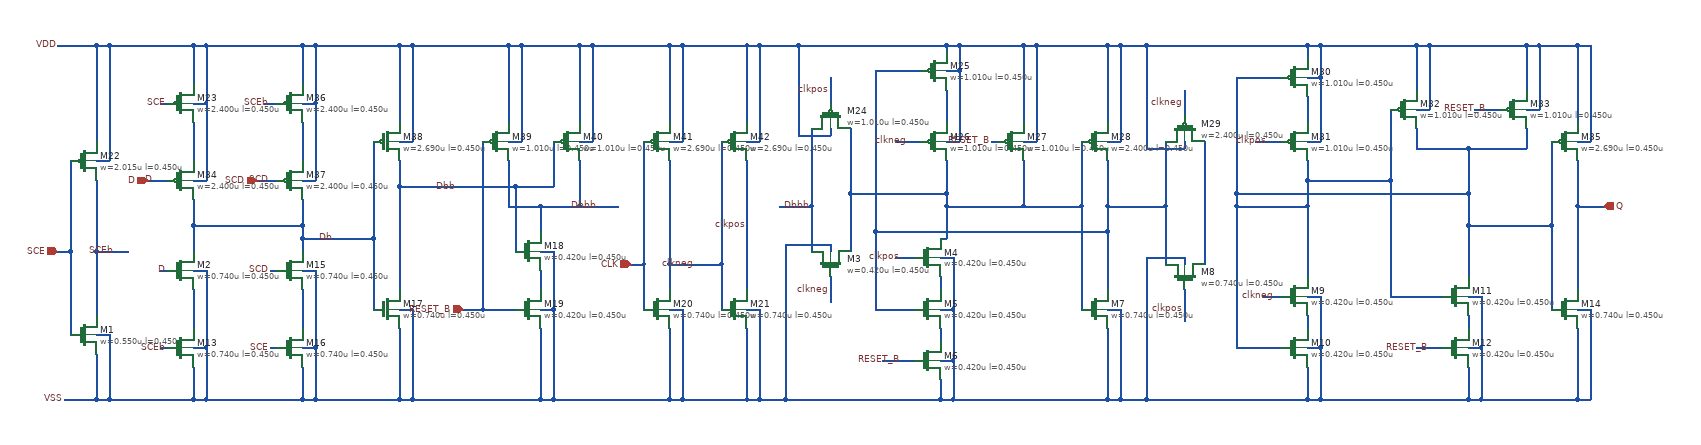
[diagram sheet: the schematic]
v {xschem version=3.4.8RC file_version=1.3}
* Copyright 2023 IHP PDK Authors
*
* Licensed under the Apache License, Version 2.0 (the "License");
* you may not use this file except in compliance with the License.
* You may obtain a copy of the License at
*
*     https://www.apache.org/licenses/LICENSE-2.0
*
* Unless required by applicable law or agreed to in writing, software
* distributed under the License is distributed on an "AS IS" BASIS,
* WITHOUT WARRANTIES OR CONDITIONS OF ANY KIND, either express or implied.
* See the License for the specific language governing permissions and
* limitations under the License.
}

G {}
K {}
V {}
S {}
F {}
E {}
N -270 -3890 -270 -3820 {lab=VSS}
N 50 -4070 50 -4050 {lab=Db}
N -250 -3920 -250 -3820 {lab=VSS}
N 70 -4370 70 -4280 {lab=VDD}
N 70 -4280 70 -4160 {lab=VDD}
N 70 -4020 70 -3900 {lab=VSS}
N 50 -4280 70 -4280 {lab=VDD}
N 50 -4370 70 -4370 {lab=VDD}
N 50 -4020 70 -4020 {lab=VSS}
N 50 -4160 70 -4160 {lab=VDD}
N 50 -3900 70 -3900 {lab=VSS}
N -320 -3820 -270 -3820 {lab=VSS}
N -100 -4370 50 -4370 {lab=VDD}
N -250 -3820 -120 -3820 {lab=VSS}
N 50 -4090 50 -4070 {lab=Db}
N 50 -4370 50 -4310 {lab=VDD}
N 50 -4250 50 -4190 {lab=#net1}
N 50 -3990 50 -3930 {lab=#net2}
N 50 -3870 50 -3820 {lab=VSS}
N -120 -4130 -120 -4090 {lab=Db}
N -120 -4090 50 -4090 {lab=Db}
N -20 -4160 10 -4160 {lab=SCD}
N -170 -3900 -160 -3900 {lab=SCEb}
N 0 -4020 10 -4020 {lab=SCD}
N 0 -3900 10 -3900 {lab=SCE}
N -100 -3820 50 -3820 {lab=VSS}
N 50 -3820 70 -3820 {lab=VSS}
N -100 -4370 -100 -4280 {lab=VDD}
N -100 -4280 -100 -4160 {lab=VDD}
N -100 -4020 -100 -3900 {lab=VSS}
N -120 -4280 -100 -4280 {lab=VDD}
N -120 -4370 -100 -4370 {lab=VDD}
N -120 -4160 -100 -4160 {lab=VDD}
N -120 -3900 -100 -3900 {lab=VSS}
N -270 -3820 -250 -3820 {lab=VSS}
N -120 -4020 -100 -4020 {lab=VSS}
N 70 -3900 70 -3820 {lab=VSS}
N -330 -4370 -270 -4370 {lab=VDD}
N 50 -4070 160 -4070 {lab=Db}
N -120 -4090 -120 -4050 {lab=Db}
N -120 -4370 -120 -4310 {lab=VDD}
N -120 -4250 -120 -4190 {lab=#net3}
N -120 -3990 -120 -3930 {lab=#net4}
N -270 -4370 -250 -4370 {lab=VDD}
N 50 -4130 50 -4090 {lab=Db}
N -190 -4160 -160 -4160 {lab=D}
N -170 -4280 -160 -4280 {lab=SCE}
N -170 -4020 -160 -4020 {lab=D}
N -10 -4280 10 -4280 {lab=SCEb}
N -310 -4050 -310 -3920 {lab=SCE}
N -250 -4370 -250 -4190 {lab=VDD}
N -270 -4190 -250 -4190 {lab=VDD}
N -270 -4050 -220 -4050 {lab=SCEb}
N -120 -3870 -120 -3820 {lab=VSS}
N -270 -3920 -250 -3920 {lab=VSS}
N -270 -4050 -270 -3950 {lab=SCEb}
N -120 -3820 -100 -3820 {lab=VSS}
N -270 -4370 -270 -4220 {lab=VDD}
N -270 -4160 -270 -4050 {lab=SCEb}
N 380 -4150 380 -4050 {lab=Dbb}
N -250 -4370 -120 -4370 {lab=VDD}
N -310 -4190 -310 -4050 {lab=SCE}
N -330 -4050 -310 -4050 {lab=SCE}
N -100 -3900 -100 -3820 {lab=VSS}
N 220 -3820 420 -3820 {lab=VSS}
N 200 -3820 220 -3820 {lab=VSS}
N 1800 -4370 1950 -4370 {lab=VDD}
N 1360 -3820 1610 -3820 {lab=VSS}
N 1780 -4370 1800 -4370 {lab=VDD}
N 1990 -4220 1990 -4090 {lab=#net5}
N 1950 -4370 1970 -4370 {lab=VDD}
N 1950 -4370 1950 -4300 {lab=VDD}
N 940 -4330 940 -4080 {lab=#net6}
N 220 -4370 370 -4370 {lab=VDD}
N 1610 -4120 1610 -4010 {lab=#net5}
N 1780 -4210 1860 -4210 {lab=#net5}
N 2050 -4370 2050 -4220 {lab=VDD}
N 1880 -3820 2030 -3820 {lab=VSS}
N 200 -3960 220 -3960 {lab=VSS}
N 1260 -4220 1260 -4120 {lab=#net7}
N 1170 -4120 1260 -4120 {lab=#net7}
N 390 -4370 480 -4370 {lab=VDD}
N 940 -4330 1010 -4330 {lab=#net6}
N 1300 -4080 1300 -3990 {lab=#net6}
N 1050 -4140 1050 -4120 {lab=#net7}
N 760 -4370 820 -4370 {lab=VDD}
N 2030 -4370 2030 -4250 {lab=VDD}
N 560 -4030 580 -4030 {lab=CLK}
N 640 -4370 740 -4370 {lab=VDD}
N 1780 -4370 1780 -4300 {lab=VDD}
N 2050 -3960 2050 -3820 {lab=VSS}
N 200 -4370 220 -4370 {lab=VDD}
N 1740 -4270 1740 -4160 {lab=#net5}
N 1880 -3980 1880 -3900 {lab=VSS}
N 1630 -3900 1630 -3820 {lab=VSS}
N 1500 -4320 1500 -4140 {lab=#net5}
N 1500 -3900 1570 -3900 {lab=#net5}
N 1040 -3930 1040 -3910 {lab=#net8}
N 1050 -4220 1070 -4220 {lab=VDD}
N 1610 -4190 1610 -4160 {lab=#net5}
N 1610 -4370 1630 -4370 {lab=VDD}
N 330 -3960 380 -3960 {lab=RESET_B}
N 1870 -4270 1910 -4270 {lab=RESET_B}
N 1780 -4240 1780 -4210 {lab=#net5}
N 1780 -3900 1820 -3900 {lab=RESET_B}
N 740 -3930 740 -3820 {lab=VSS}
N 740 -3820 760 -3820 {lab=VSS}
N 1970 -4370 1970 -4270 {lab=VDD}
N 1740 -3980 1820 -3980 {lab=#net5}
N 1610 -4160 1740 -4160 {lab=#net5}
N 1630 -4370 1780 -4370 {lab=VDD}
N 1860 -3900 1880 -3900 {lab=VSS}
N 1800 -4370 1800 -4270 {lab=VDD}
N 1610 -4160 1610 -4120 {lab=#net5}
N 1860 -3820 1880 -3820 {lab=VSS}
N 1630 -4320 1630 -4220 {lab=VDD}
N 200 -4150 380 -4150 {lab=Dbb}
N 1780 -4270 1800 -4270 {lab=VDD}
N 1860 -3980 1880 -3980 {lab=VSS}
N 1950 -4240 1950 -4210 {lab=#net5}
N 1860 -3950 1860 -3930 {lab=#net9}
N 1860 -4090 1860 -4010 {lab=#net5}
N 1950 -4270 1970 -4270 {lab=VDD}
N 1610 -3870 1610 -3820 {lab=VSS}
N 620 -3820 640 -3820 {lab=VSS}
N 1610 -3820 1630 -3820 {lab=VSS}
N 1860 -4210 1860 -4140 {lab=#net5}
N 1530 -4220 1570 -4220 {lab=clkpos}
N 1630 -4370 1630 -4320 {lab=VDD}
N 1500 -4140 1860 -4140 {lab=#net5}
N 1450 -4220 1450 -4030 {lab=#net5}
N 1360 -4040 1360 -3820 {lab=VSS}
N 200 -4190 200 -4150 {lab=Dbb}
N 1880 -3900 1880 -3820 {lab=VSS}
N 1610 -3980 1630 -3980 {lab=VSS}
N 1860 -4140 1860 -4090 {lab=#net5}
N 1610 -3900 1630 -3900 {lab=VSS}
N 1050 -4300 1050 -4250 {lab=#net10}
N 1540 -3980 1570 -3980 {lab=clkneg}
N 1610 -4370 1610 -4350 {lab=VDD}
N 1860 -3870 1860 -3820 {lab=VSS}
N 940 -4080 1300 -4080 {lab=#net6}
N 1610 -4290 1610 -4250 {lab=#net11}
N 1320 -3820 1360 -3820 {lab=VSS}
N 1610 -4220 1630 -4220 {lab=VDD}
N 1610 -4320 1630 -4320 {lab=VDD}
N 1630 -3820 1860 -3820 {lab=VSS}
N 1420 -4220 1420 -4210 {lab=VDD}
N 1500 -4120 1500 -3900 {lab=#net5}
N 1420 -4040 1420 -4030 {lab=VSS}
N 1300 -4370 1320 -4370 {lab=VDD}
N 1320 -4370 1320 -4220 {lab=VDD}
N 1420 -4300 1420 -4260 {lab=clkneg}
N 1420 -3990 1420 -3940 {lab=clkpos}
N 1630 -3980 1630 -3900 {lab=VSS}
N 940 -4080 940 -3960 {lab=#net6}
N 1060 -3820 1300 -3820 {lab=VSS}
N 1740 -4160 1740 -3980 {lab=#net5}
N 330 -4220 330 -3960 {lab=RESET_B}
N 1320 -3960 1320 -3820 {lab=VSS}
N 1390 -4120 1390 -4030 {lab=#net6}
N 760 -3820 800 -3820 {lab=VSS}
N 1060 -4040 1060 -3960 {lab=VSS}
N 1500 -4320 1570 -4320 {lab=#net5}
N 200 -4220 220 -4220 {lab=VDD}
N 1300 -3960 1320 -3960 {lab=VSS}
N 1300 -4220 1320 -4220 {lab=VDD}
N 1050 -4370 1070 -4370 {lab=VDD}
N 160 -4070 160 -3960 {lab=Db}
N 940 -3960 1000 -3960 {lab=#net6}
N 1300 -4370 1300 -4250 {lab=VDD}
N 970 -4220 1010 -4220 {lab=clkneg}
N 970 -4040 1000 -4040 {lab=clkpos}
N 950 -3880 1000 -3880 {lab=RESET_B}
N 1300 -4120 1300 -4080 {lab=#net6}
N 1120 -4220 1130 -4220 {lab=RESET_B}
N 1060 -3960 1060 -3880 {lab=VSS}
N 2030 -3820 2050 -3820 {lab=VSS}
N 1170 -4190 1170 -4120 {lab=#net7}
N 300 -3960 330 -3960 {lab=RESET_B}
N 2030 -3930 2030 -3820 {lab=VSS}
N 620 -4370 620 -4250 {lab=VDD}
N 740 -4370 740 -4250 {lab=VDD}
N 500 -4370 620 -4370 {lab=VDD}
N 1070 -4330 1070 -4220 {lab=VDD}
N 1300 -3820 1320 -3820 {lab=VSS}
N 1190 -4370 1300 -4370 {lab=VDD}
N 1060 -3880 1060 -3820 {lab=VSS}
N 1050 -4190 1050 -4140 {lab=#net7}
N 1050 -4330 1070 -4330 {lab=VDD}
N 1170 -4220 1190 -4220 {lab=VDD}
N 480 -4120 540 -4120 {lab=Dbbb}
N 1040 -4070 1050 -4070 {lab=#net7}
N 640 -3820 740 -3820 {lab=VSS}
N 1070 -4370 1070 -4330 {lab=VDD}
N 1050 -4370 1050 -4360 {lab=VDD}
N 870 -4010 870 -3970 {lab=clkneg}
N 870 -4320 870 -4280 {lab=clkpos}
N 1190 -4370 1190 -4220 {lab=VDD}
N 220 -4370 220 -4220 {lab=VDD}
N 1360 -4370 1610 -4370 {lab=VDD}
N 1040 -3880 1060 -3880 {lab=VSS}
N 1040 -3960 1060 -3960 {lab=VSS}
N 1040 -4040 1060 -4040 {lab=VSS}
N 1040 -4010 1040 -3990 {lab=#net12}
N 800 -4060 800 -3820 {lab=VSS}
N 840 -4120 840 -4050 {lab=Dbbb}
N 1170 -4370 1190 -4370 {lab=VDD}
N 870 -4060 870 -4050 {lab=VSS}
N 870 -4240 870 -4230 {lab=VDD}
N 900 -4140 900 -4050 {lab=#net7}
N 840 -4240 840 -4120 {lab=Dbbb}
N 800 -3820 1040 -3820 {lab=VSS}
N 200 -3930 200 -3820 {lab=VSS}
N 200 -4370 200 -4250 {lab=VDD}
N 2030 -4370 2050 -4370 {lab=VDD}
N 2030 -4190 2030 -4120 {lab=Q}
N 1990 -4090 1990 -3960 {lab=#net5}
N 2030 -4120 2070 -4120 {lab=Q}
N 620 -3930 620 -3820 {lab=VSS}
N 620 -4030 700 -4030 {lab=clkneg}
N 2030 -4220 2050 -4220 {lab=VDD}
N 2030 -3960 2050 -3960 {lab=VSS}
N 1040 -3820 1060 -3820 {lab=VSS}
N 760 -3960 760 -3820 {lab=VSS}
N 2030 -4120 2030 -3990 {lab=Q}
N 620 -4190 620 -4030 {lab=clkneg}
N 1040 -3850 1040 -3820 {lab=VSS}
N 70 -3820 200 -3820 {lab=VSS}
N 1860 -4210 1950 -4210 {lab=#net5}
N 1610 -3950 1610 -3930 {lab=#net13}
N 1970 -4370 2030 -4370 {lab=VDD}
N 1300 -4190 1300 -4120 {lab=#net6}
N 740 -4190 740 -3990 {lab=clkpos}
N 640 -3960 640 -3820 {lab=VSS}
N 420 -4120 420 -4080 {lab=Dbbb}
N 370 -4190 370 -4120 {lab=Dbbb}
N 640 -4370 640 -4220 {lab=VDD}
N 1050 -4120 1050 -4070 {lab=#net7}
N 620 -4370 640 -4370 {lab=VDD}
N 390 -4370 390 -4220 {lab=VDD}
N 580 -4030 580 -3960 {lab=CLK}
N 1860 -4090 1990 -4090 {lab=#net5}
N 580 -4220 580 -4030 {lab=CLK}
N 420 -3930 420 -3820 {lab=VSS}
N 200 -4150 200 -3990 {lab=Dbb}
N 1050 -4120 1170 -4120 {lab=#net7}
N 420 -3820 440 -3820 {lab=VSS}
N 700 -4220 700 -4030 {lab=clkneg}
N 370 -4370 370 -4250 {lab=VDD}
N 220 -3960 220 -3820 {lab=VSS}
N 160 -4220 160 -4070 {lab=Db}
N 820 -4370 1050 -4370 {lab=VDD}
N 620 -4030 620 -3990 {lab=clkneg}
N 620 -4220 640 -4220 {lab=VDD}
N 740 -4220 760 -4220 {lab=VDD}
N 740 -3960 760 -3960 {lab=VSS}
N 620 -3960 640 -3960 {lab=VSS}
N 370 -4370 390 -4370 {lab=VDD}
N 420 -3960 440 -3960 {lab=VSS}
N 370 -4120 420 -4120 {lab=Dbbb}
N 500 -4370 500 -4220 {lab=VDD}
N 370 -4220 390 -4220 {lab=VDD}
N 480 -4370 500 -4370 {lab=VDD}
N 440 -3820 620 -3820 {lab=VSS}
N 440 -4050 440 -3960 {lab=VSS}
N 700 -4030 700 -3960 {lab=clkneg}
N 480 -4190 480 -4120 {lab=Dbbb}
N 480 -4370 480 -4250 {lab=VDD}
N 1070 -4370 1170 -4370 {lab=VDD}
N 1320 -4370 1360 -4370 {lab=VDD}
N 1300 -3930 1300 -3820 {lab=VSS}
N 440 -4220 440 -4150 {lab=Dbb}
N 420 -4120 480 -4120 {lab=Dbbb}
N 380 -4150 440 -4150 {lab=Dbb}
N 440 -3960 440 -3820 {lab=VSS}
N 480 -4220 500 -4220 {lab=VDD}
N 420 -4050 440 -4050 {lab=VSS}
N 420 -4020 420 -3990 {lab=#net14}
N 1260 -4120 1260 -3960 {lab=#net7}
N 70 -4370 200 -4370 {lab=VDD}
N 1170 -4370 1170 -4250 {lab=VDD}
N 1500 -4120 1610 -4120 {lab=#net5}
N 1500 -4140 1500 -4120 {lab=#net5}
N 1300 -4120 1390 -4120 {lab=#net6}
N 1390 -4220 1390 -4120 {lab=#net6}
N 1360 -4040 1420 -4040 {lab=VSS}
N 1360 -4210 1420 -4210 {lab=VDD}
N 1360 -4370 1360 -4210 {lab=VDD}
N 760 -4370 760 -4220 {lab=VDD}
N 740 -4370 760 -4370 {lab=VDD}
N 820 -4370 820 -4230 {lab=VDD}
N 820 -4230 870 -4230 {lab=VDD}
N 790 -4120 840 -4120 {lab=Dbbb}
N 900 -4140 1050 -4140 {lab=#net7}
N 900 -4240 900 -4140 {lab=#net7}
N 800 -4060 870 -4060 {lab=VSS}
C {lab_wire.sym} 0 -4160 0 0 {name=l1 sig_type=std_logic lab=SCD}
C {lab_wire.sym} -160 -3900 0 0 {name=l2 sig_type=std_logic lab=SCEb}
C {lab_wire.sym} 0 -4020 0 0 {name=l3 sig_type=std_logic lab=SCD}
C {lab_wire.sym} 0 -3900 0 0 {name=l4 sig_type=std_logic lab=SCE}
C {lab_wire.sym} 100 -4070 0 0 {name=l5 sig_type=std_logic lab=Db}
C {lab_wire.sym} -180 -4160 0 0 {name=l6 sig_type=std_logic lab=D}
C {lab_wire.sym} -160 -4280 0 0 {name=l7 sig_type=std_logic lab=SCE}
C {lab_wire.sym} -160 -4020 0 0 {name=l8 sig_type=std_logic lab=D}
C {lab_wire.sym} 0 -4280 0 0 {name=l9 sig_type=std_logic lab=SCEb}
C {lab_wire.sym} -240 -4050 0 0 {name=l10 sig_type=std_logic lab=SCEb}
C {lab_wire.sym} 1890 -4270 0 0 {name=l11 sig_type=std_logic lab=RESET_B}
C {lab_wire.sym} 1800 -3900 0 0 {name=l12 sig_type=std_logic lab=RESET_B}
C {lab_wire.sym} 290 -4150 0 0 {name=l13 sig_type=std_logic lab=Dbb}
C {lab_wire.sym} 1550 -4220 0 0 {name=l14 sig_type=std_logic lab=clkpos}
C {lab_wire.sym} 1560 -3980 0 0 {name=l15 sig_type=std_logic lab=clkneg}
C {lab_wire.sym} 1420 -4280 0 0 {name=l16 sig_type=std_logic lab=clkneg}
C {lab_wire.sym} 1420 -3960 0 0 {name=l17 sig_type=std_logic lab=clkpos}
C {lab_wire.sym} 990 -4220 0 0 {name=l18 sig_type=std_logic lab=clkneg}
C {lab_wire.sym} 980 -4040 0 0 {name=l19 sig_type=std_logic lab=clkpos}
C {lab_wire.sym} 980 -3880 0 0 {name=l20 sig_type=std_logic lab=RESET_B}
C {lab_wire.sym} 1120 -4220 0 0 {name=l21 sig_type=std_logic lab=RESET_B}
C {lab_wire.sym} 510 -4120 0 0 {name=l22 sig_type=std_logic lab=Dbbb}
C {lab_wire.sym} 870 -3990 0 0 {name=l23 sig_type=std_logic lab=clkneg}
C {lab_wire.sym} 870 -4300 0 0 {name=l24 sig_type=std_logic lab=clkpos}
C {lab_wire.sym} 840 -4120 0 0 {name=l25 sig_type=std_logic lab=Dbbb}
C {lab_wire.sym} 660 -4030 0 0 {name=l26 sig_type=std_logic lab=clkneg}
C {lab_wire.sym} 740 -4090 0 0 {name=l27 sig_type=std_logic lab=clkpos}
C {devices/opin.sym} 2070 -4120 0 0 {name=p7 lab=Q}
C {devices/ipin.sym} 560 -4030 0 0 {name=p6 lab=CLK}
C {devices/ipin.sym} -190 -4160 0 0 {name=p2 lab=D}
C {devices/ipin.sym} 300 -3960 0 0 {name=p1 lab=RESET_B}
C {devices/ipin.sym} -20 -4160 0 0 {name=p5 lab=SCD}
C {devices/ipin.sym} -330 -4050 0 0 {name=p4 lab=SCE}
C {devices/lab_pin.sym} -330 -4370 0 0 {name=p3 sig_type=std_logic lab=VDD}
C {devices/lab_pin.sym} -320 -3820 0 0 {name=p8 sig_type=std_logic lab=VSS}
C {sg13_hv_nmos.sym} -290 -3920 0 0 {name=M1 w=0.550u l=0.450u ng=1 m=1 model=sg13_hv_nmos}
C {sg13_hv_nmos.sym} -140 -4020 0 0 {name=M2 w=0.740u l=0.450u ng=1 m=1 model=sg13_hv_nmos}
C {sg13_hv_nmos.sym} 870 -4030 3 0 {name=M3 w=0.420u l=0.450u ng=1 m=1 model=sg13_hv_nmos}
C {sg13_hv_nmos.sym} 1020 -4040 0 0 {name=M4 w=0.420u l=0.450u ng=1 m=1 model=sg13_hv_nmos}
C {sg13_hv_nmos.sym} 1020 -3960 0 0 {name=M5 w=0.420u l=0.450u ng=1 m=1 model=sg13_hv_nmos}
C {sg13_hv_nmos.sym} 1020 -3880 0 0 {name=M6 w=0.420u l=0.450u ng=1 m=1 model=sg13_hv_nmos}
C {sg13_hv_nmos.sym} 1280 -3960 0 0 {name=M7 w=0.740u l=0.450u ng=1 m=1 model=sg13_hv_nmos}
C {sg13_hv_nmos.sym} 1420 -4010 3 0 {name=M8 w=0.740u l=0.450u ng=1 m=1 model=sg13_hv_nmos}
C {sg13_hv_nmos.sym} 1590 -3980 0 0 {name=M9 w=0.420u l=0.450u ng=1 m=1 model=sg13_hv_nmos}
C {sg13_hv_nmos.sym} 1590 -3900 0 0 {name=M10 w=0.420u l=0.450u ng=1 m=1 model=sg13_hv_nmos}
C {sg13_hv_nmos.sym} 1840 -3980 0 0 {name=M11 w=0.420u l=0.450u ng=1 m=1 model=sg13_hv_nmos}
C {sg13_hv_nmos.sym} 1840 -3900 0 0 {name=M12 w=0.420u l=0.450u ng=1 m=1 model=sg13_hv_nmos}
C {sg13_hv_nmos.sym} -140 -3900 0 0 {name=M13 w=0.740u l=0.450u ng=1 m=1 model=sg13_hv_nmos}
C {sg13_hv_nmos.sym} 2010 -3960 0 0 {name=M14 w=0.740u l=0.450u ng=1 m=1 model=sg13_hv_nmos}
C {sg13_hv_nmos.sym} 30 -4020 0 0 {name=M15 w=0.740u l=0.450u ng=1 m=1 model=sg13_hv_nmos}
C {sg13_hv_nmos.sym} 30 -3900 0 0 {name=M16 w=0.740u l=0.450u ng=1 m=1 model=sg13_hv_nmos}
C {sg13_hv_nmos.sym} 180 -3960 0 0 {name=M17 w=0.740u l=0.450u ng=1 m=1 model=sg13_hv_nmos}
C {sg13_hv_nmos.sym} 400 -4050 0 0 {name=M18 w=0.420u l=0.450u ng=1 m=1 model=sg13_hv_nmos}
C {sg13_hv_nmos.sym} 400 -3960 0 0 {name=M19 w=0.420u l=0.450u ng=1 m=1 model=sg13_hv_nmos}
C {sg13_hv_nmos.sym} 600 -3960 0 0 {name=M20 w=0.740u l=0.450u ng=1 m=1 model=sg13_hv_nmos}
C {sg13_hv_nmos.sym} 720 -3960 0 0 {name=M21 w=0.740u l=0.450u ng=1 m=1 model=sg13_hv_nmos}
C {sg13_hv_pmos.sym} -290 -4190 0 0 {name=M22 w=2.015u l=0.450u ng=1 m=1 model=sg13_hv_pmos}
C {sg13_hv_pmos.sym} -140 -4280 0 0 {name=M23 w=2.400u l=0.450u ng=1 m=1 model=sg13_hv_pmos}
C {sg13_hv_pmos.sym} 870 -4260 1 0 {name=M24 w=1.010u l=0.450u ng=1 m=1 model=sg13_hv_pmos}
C {sg13_hv_pmos.sym} 1030 -4330 0 0 {name=M25 w=1.010u l=0.450u ng=1 m=1 model=sg13_hv_pmos}
C {sg13_hv_pmos.sym} 1030 -4220 0 0 {name=M26 w=1.010u l=0.450u ng=1 m=1 model=sg13_hv_pmos}
C {sg13_hv_pmos.sym} 1150 -4220 0 0 {name=M27 w=1.010u l=0.450u ng=1 m=1 model=sg13_hv_pmos}
C {sg13_hv_pmos.sym} 1280 -4220 0 0 {name=M28 w=2.400u l=0.450u ng=1 m=1 model=sg13_hv_pmos}
C {sg13_hv_pmos.sym} 1420 -4240 1 0 {name=M29 w=2.400u l=0.450u ng=1 m=1 model=sg13_hv_pmos}
C {sg13_hv_pmos.sym} 1590 -4320 0 0 {name=M30 w=1.010u l=0.450u ng=1 m=1 model=sg13_hv_pmos}
C {sg13_hv_pmos.sym} 1590 -4220 0 0 {name=M31 w=1.010u l=0.450u ng=1 m=1 model=sg13_hv_pmos}
C {sg13_hv_pmos.sym} 1760 -4270 0 0 {name=M32 w=1.010u l=0.450u ng=1 m=1 model=sg13_hv_pmos}
C {sg13_hv_pmos.sym} 1930 -4270 0 0 {name=M33 w=1.010u l=0.450u ng=1 m=1 model=sg13_hv_pmos}
C {sg13_hv_pmos.sym} -140 -4160 0 0 {name=M34 w=2.400u l=0.450u ng=1 m=1 model=sg13_hv_pmos}
C {sg13_hv_pmos.sym} 2010 -4220 0 0 {name=M35 w=2.690u l=0.450u ng=1 m=1 model=sg13_hv_pmos}
C {sg13_hv_pmos.sym} 30 -4280 0 0 {name=M36 w=2.400u l=0.450u ng=1 m=1 model=sg13_hv_pmos}
C {sg13_hv_pmos.sym} 30 -4160 0 0 {name=M37 w=2.400u l=0.450u ng=1 m=1 model=sg13_hv_pmos}
C {sg13_hv_pmos.sym} 180 -4220 0 0 {name=M38 w=2.690u l=0.450u ng=1 m=1 model=sg13_hv_pmos}
C {sg13_hv_pmos.sym} 350 -4220 0 0 {name=M39 w=1.010u l=0.450u ng=1 m=1 model=sg13_hv_pmos}
C {sg13_hv_pmos.sym} 460 -4220 0 0 {name=M40 w=1.010u l=0.450u ng=1 m=1 model=sg13_hv_pmos}
C {sg13_hv_pmos.sym} 600 -4220 0 0 {name=M41 w=2.690u l=0.450u ng=1 m=1 model=sg13_hv_pmos}
C {sg13_hv_pmos.sym} 720 -4220 0 0 {name=M42 w=2.690u l=0.450u ng=1 m=1 model=sg13_hv_pmos}
C {devices/title-2.sym} -840 -2880 0 0 {name=l1 author="IHP PDK AUTHORS"}
